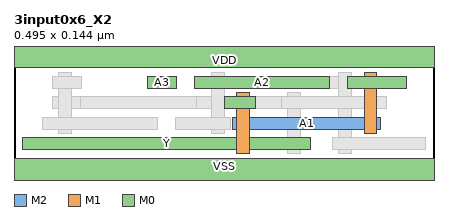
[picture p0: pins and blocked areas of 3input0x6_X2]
MACRO 3input0x6_X2
  CLASS CORE ;
  ORIGIN 0 0 ;
  FOREIGN 3input0x6_X2 0 0 ;
  SIZE 0.4950 BY 0.1440 ;
  SYMMETRY X Y ;
  SITE coresite ;
  PIN A1
    DIRECTION INPUT ;
    USE SIGNAL ;
    PORT
      LAYER M2 ;
        RECT 0.2580 0.0530 0.4320 0.0670 ;
      LAYER M1 ;
        RECT 0.2625 0.0240 0.2775 0.0960 ;
        RECT 0.4125 0.0480 0.4275 0.1200 ;
      LAYER M0 ;
        RECT 0.3930 0.1010 0.4620 0.1150 ;
        RECT 0.2475 0.0770 0.2850 0.0910 ;
    END
  END A1
  PIN A2
    DIRECTION INPUT ;
    USE SIGNAL ;
    PORT
      LAYER M0 ;
        RECT 0.2130 0.1010 0.3720 0.1150 ;
    END
  END A2
  PIN A3
    DIRECTION INPUT ;
    USE SIGNAL ;
    PORT
      LAYER M0 ;
        RECT 0.1575 0.1010 0.1920 0.1150 ;
    END
  END A3
  PIN Y
    DIRECTION OUTPUT ;
    USE SIGNAL ;
    PORT
      LAYER M0 ;
        RECT 0.0105 0.0290 0.3495 0.0430 ;
    END
  END Y
  PIN VDD
    DIRECTION INOUT ;
    USE POWER ;
    SHAPE ABUTMENT ;
    PORT
      LAYER M0 ;
        RECT 0.0000 0.1260 0.4950 0.1620 ;
    END
  END VDD
  PIN VSS
    DIRECTION INOUT ;
    USE GROUND ;
    SHAPE ABUTMENT ;
    PORT
      LAYER M0 ;
        RECT 0.0000 -0.0180 0.4950 0.0180 ;
    END
  END VSS
  OBS
    LAYER M2 ;
      RECT 0.0450 0.0770 0.3420 0.0910 ;
      RECT 0.2250 0.1010 0.4050 0.1150 ;
    LAYER V1 ;
      RECT 0.0530 0.0770 0.0670 0.0910 ;
      RECT 0.3230 0.0770 0.3370 0.0910 ;
      RECT 0.2630 0.0530 0.2770 0.0670 ;
      RECT 0.4130 0.0530 0.4270 0.0670 ;
      RECT 0.2330 0.1010 0.2470 0.1150 ;
      RECT 0.3830 0.1010 0.3970 0.1150 ;
    LAYER M1 ;
      RECT 0.3225 0.0240 0.3375 0.0960 ;
      RECT 0.0525 0.0480 0.0675 0.1200 ;
      RECT 0.2325 0.0480 0.2475 0.1200 ;
      RECT 0.3825 0.0240 0.3975 0.1200 ;
    LAYER V0 ;
      RECT 0.0530 0.1010 0.0670 0.1150 ;
      RECT 0.3230 0.0770 0.3370 0.0910 ;
      RECT 0.2630 0.0770 0.2770 0.0910 ;
      RECT 0.4130 0.1010 0.4270 0.1150 ;
      RECT 0.2330 0.0530 0.2470 0.0670 ;
      RECT 0.3830 0.0290 0.3970 0.0430 ;
    LAYER M0 ;
      RECT 0.3750 0.0290 0.4845 0.0430 ;
      RECT 0.0330 0.0530 0.1695 0.0670 ;
      RECT 0.1905 0.0530 0.2550 0.0670 ;
      RECT 0.2805 0.0530 0.3945 0.0670 ;
      RECT 0.0780 0.0770 0.2145 0.0910 ;
      RECT 0.3150 0.0770 0.4395 0.0910 ;
      RECT 0.0450 0.1010 0.0795 0.1150 ;
  END
END 3input0x6_X2
